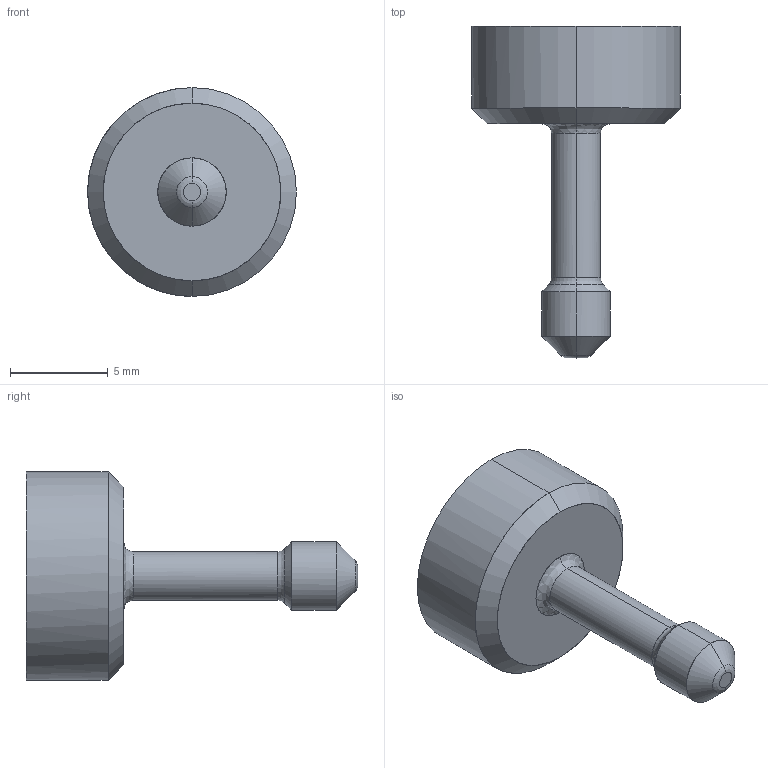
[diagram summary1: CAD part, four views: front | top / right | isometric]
IGES file: header records copied from the file, then geometry measured from it (millimetres).
Start section: START RECORD GO HERE.
Global section: file name: ia100720.igs; native system: DASSAULT SYSTEMES CATIA V5 R20 - www.3ds.com; preprocessor: CATIA Version 5 Release 20 ; author: Utente; organization: NB04-ASUS; date: 20201108.074425; units: millimetre
Bounding box: 10.7 x 17 x 10.7 mm (x, y, z)
Surface area: 448.9 mm2 (no closed solid volume)
Topology: 0 solids, 0 shells, 58 faces, 278 edges, 278 vertices
Faces by surface type: revolution 36, plane 22
